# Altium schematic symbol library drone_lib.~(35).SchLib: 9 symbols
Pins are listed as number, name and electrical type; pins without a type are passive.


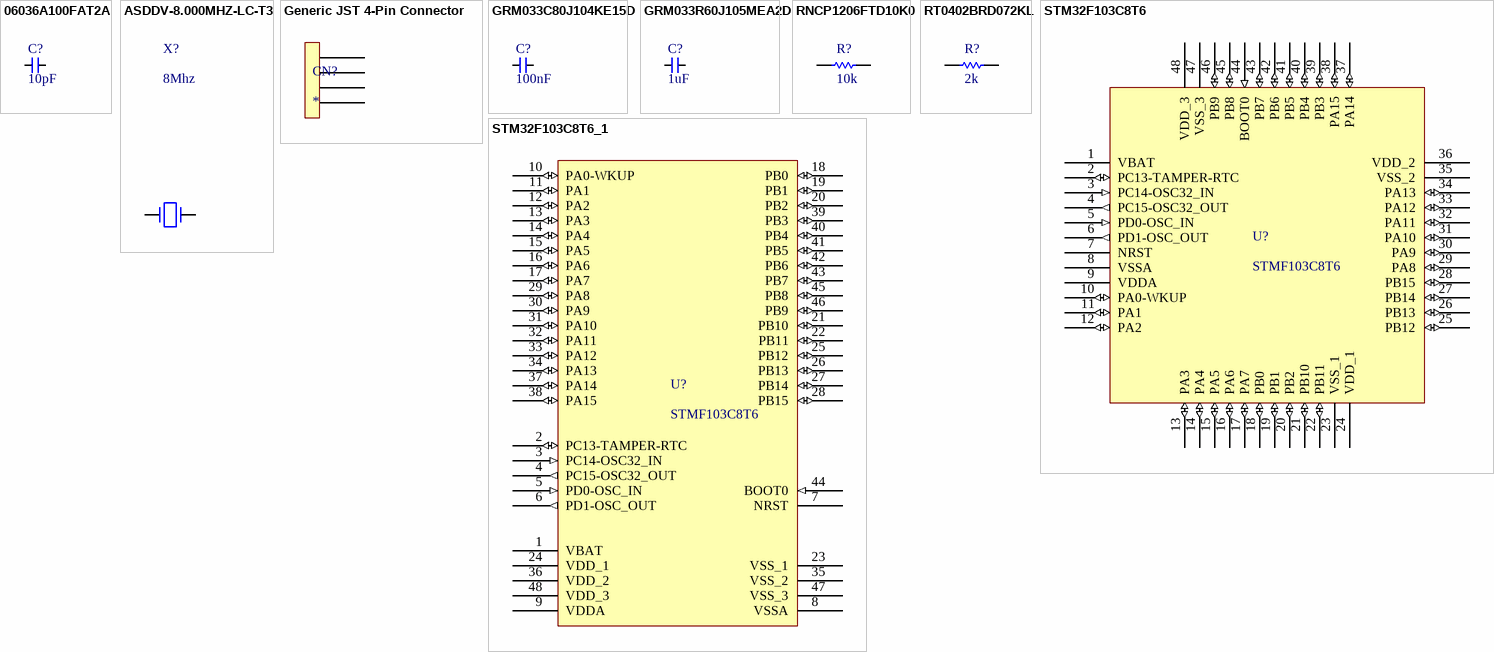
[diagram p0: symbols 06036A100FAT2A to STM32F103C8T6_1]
## 06036A100FAT2A
designator C?, comment 10pF
Ceramic Capacitor, Ceramic, 6.3V, 1% +Tol, 1% -Tol, C0G, -/+30ppm/Cel TC, 0.00001uF, Surface Mount, 0603; Manufacturer: Kyocera AVX; Manufacturer Part Number: 06036A100FAT2A; Multilayer: No
pins: 1, 2

## ASDDV-8.000MHZ-LC-T3
designator X?, comment 8Mhz
Osc, 8MHZ, Cmos/hcmos/lvcmos, SMD Rohs Compliant: Yes; Manufacturer: Abracon; Manufacturer Part Number: ASDDV-8.000MHZ-LC-T3
pins: 1, 2

## Generic JST 4-Pin Connector
designator CN?
pins: 1, 2, 3, 4

## GRM033C80J104KE15D
designator C?, comment 100nF
Ceramic Capacitor, Multilayer, Ceramic, 6.3V, 10% +Tol, 10% -Tol, X6S, 22% TC, 0.1uF, Surface Mount, 0201; Manufacturer: Murata; Manufacturer Part Number: GRM033C80J104KE15D; Multilayer: Yes
pins: 1, 2

## GRM033R60J105MEA2D
designator C?, comment 1uF
Ceramic Capacitor, Multilayer, Ceramic, 6.3V, 20% +Tol, 20% -Tol, X5R, 15% TC, 1uF, Surface Mount, 0201; Manufacturer: Murata; Manufacturer Part Number: GRM033R60J105MEA2D; Multilayer: Yes
pins: 1, 2

## RNCP1206FTD10K0
designator R?, comment 10k
Fixed Resistor, Thin Film, 0.5W, 10000ohm, 200V, 1% +/-Tol, 100ppm/Cel, Surface Mount, 1206; Manufacturer: Stackpole Electronics; Manufacturer Part Number: RNCP1206FTD10K0; Additional Feature: ANTI-SULFUR; Power: 500mW; Rated Temperature: 70°C; Value: 10kR; Temperature Coefficient (ppm/Cel): 100; Package Height: 0.5mm; Package Length: 3.1mm; Package Width: 1.5mm
pins: 2, 4

## RT0402BRD072KL
designator R?, comment 2k
Fixed Resistor, Thin Film, 0.0625W, 2000ohm, 50V, 0.1% +/-Tol, 25ppm/Cel, Surface Mount, 0402; Manufacturer: Yageo; Manufacturer Part Number: RT0402BRD072KL; Additional Feature: HIGH PRECISION; Power: 62.5mW; Rated Temperature: 70°C; Temperature Coefficient (ppm/Cel): 25; Package Height: 0.3mm; Package Length: 1mm; Package Width: 0.5mm
pins: 2, 4

## STM32F103C8T6
designator U?, comment STMF103C8T6
ARM Cortex-M3 STM32 F1 Microcontroller 32-Bit 72MHz 64kB FLASH LQFP48 STM32F103C8T6; Manufacturer: STMicroelectronics; Package Body Material: Plastic; Clock Frequency: 16MHz; Number of I/O Lines: 37; Package Equivalence Code: QFP48,.35SQ,20; Power Supplies: 2.5/3.3; Max Supply Current: 50mA; Max Supply Voltage: 3.6V; Min Supply Voltage: 2V; Nominal Supply Voltage: 3.3V; Time @ Peak Reflow Temperature-Max (s): 30s; Peripherals: POR; Interface: I2C; Qualification Status: Not Qualified
pins: 1 VBAT (power), 2 PC13-TAMPER-RTC (io), 3 PC14-OSC32_IN (in), 4 PC15-OSC32_OUT (out), 5 PD0-OSC_IN (in), 6 PD1-OSC_OUT (out), 7 NRST, 8 VSSA (power), 9 VDDA (power), 10 PA0-WKUP (io), 11 PA1 (io), 12 PA2 (io), 13 PA3 (io), 14 PA4 (io), 15 PA5 (io), 16 PA6 (io), 17 PA7 (io), 18 PB0 (io), 19 PB1 (io), 20 PB2 (io), 21 PB10 (io), 22 PB11 (io), 23 VSS_1 (power), 24 VDD_1 (power), 25 PB12 (io), 26 PB13 (io), 27 PB14 (io), 28 PB15 (io), 29 PA8 (io), 30 PA9 (io), 31 PA10 (io), 32 PA11 (io), 33 PA12 (io), 34 PA13 (io), 35 VSS_2 (power), 36 VDD_2 (power), 37 PA14 (io), 38 PA15 (io), 39 PB3 (io), 40 PB4 (io), 41 PB5 (io), 42 PB6 (io), 43 PB7 (io), 44 BOOT0 (in), 45 PB8 (io), 46 PB9 (io), 47 VSS_3 (power), 48 VDD_3 (power)

## STM32F103C8T6_1
designator U?, comment STMF103C8T6
ARM Cortex-M3 STM32 F1 Microcontroller 32-Bit 72MHz 64kB FLASH LQFP48 STM32F103C8T6; Manufacturer: STMicroelectronics; Package Body Material: Plastic; Clock Frequency: 16MHz; Number of I/O Lines: 37; Package Equivalence Code: QFP48,.35SQ,20; Power Supplies: 2.5/3.3; Max Supply Current: 50mA; Max Supply Voltage: 3.6V; Min Supply Voltage: 2V; Nominal Supply Voltage: 3.3V; Time @ Peak Reflow Temperature-Max (s): 30s; Peripherals: POR; Interface: I2C; Qualification Status: Not Qualified
pins: 1 VBAT (power), 2 PC13-TAMPER-RTC (io), 3 PC14-OSC32_IN (in), 4 PC15-OSC32_OUT (out), 5 PD0-OSC_IN (in), 6 PD1-OSC_OUT (out), 7 NRST, 8 VSSA (power), 9 VDDA (power), 10 PA0-WKUP (io), 11 PA1 (io), 12 PA2 (io), 13 PA3 (io), 14 PA4 (io), 15 PA5 (io), 16 PA6 (io), 17 PA7 (io), 18 PB0 (io), 19 PB1 (io), 20 PB2 (io), 21 PB10 (io), 22 PB11 (io), 23 VSS_1 (power), 24 VDD_1 (power), 25 PB12 (io), 26 PB13 (io), 27 PB14 (io), 28 PB15 (io), 29 PA8 (io), 30 PA9 (io), 31 PA10 (io), 32 PA11 (io), 33 PA12 (io), 34 PA13 (io), 35 VSS_2 (power), 36 VDD_2 (power), 37 PA14 (io), 38 PA15 (io), 39 PB3 (io), 40 PB4 (io), 41 PB5 (io), 42 PB6 (io), 43 PB7 (io), 44 BOOT0 (in), 45 PB8 (io), 46 PB9 (io), 47 VSS_3 (power), 48 VDD_3 (power)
